VERSION 5.7 ;
  NOWIREEXTENSIONATPIN ON ;
  DIVIDERCHAR "/" ;
  BUSBITCHARS "[]" ;
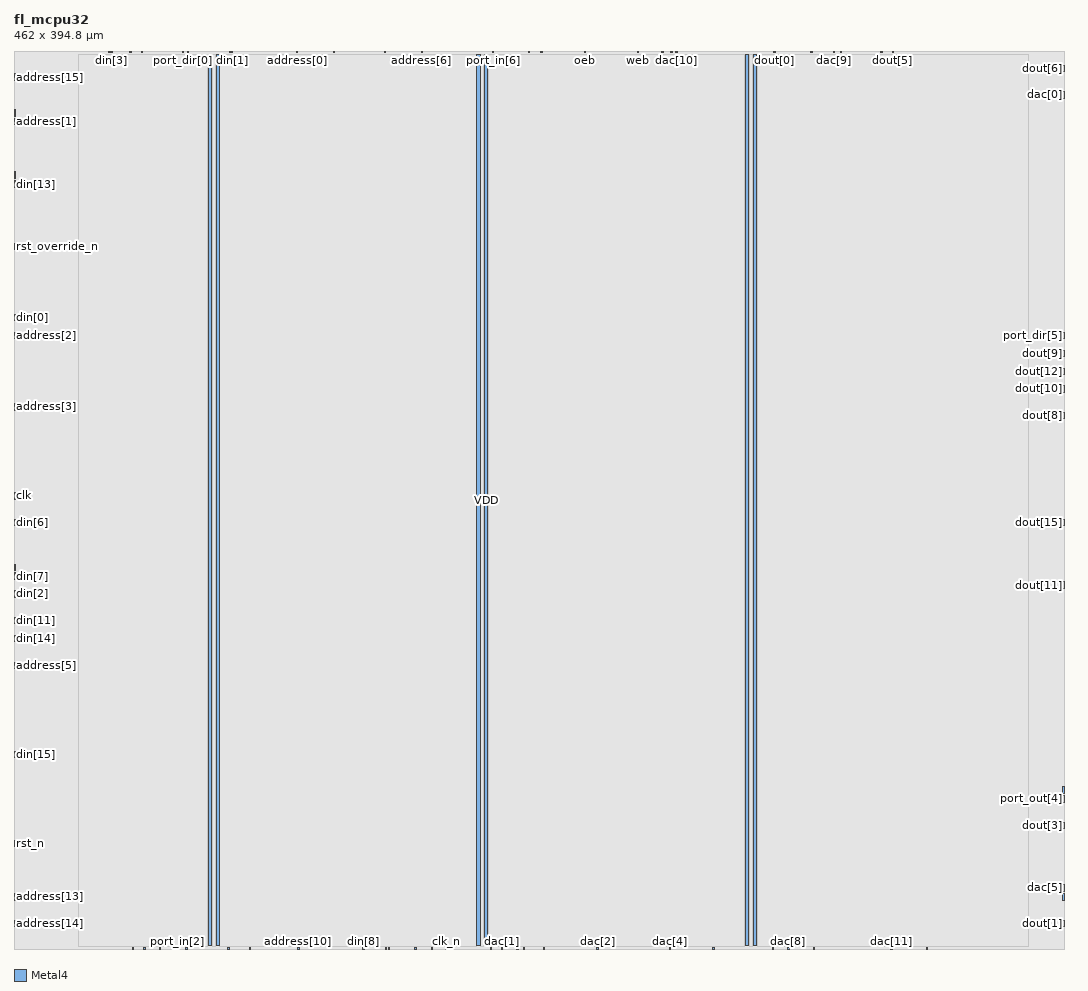
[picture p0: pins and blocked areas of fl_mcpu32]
MACRO fl_mcpu32
  CLASS BLOCK ;
  FOREIGN fl_mcpu32 ;
  ORIGIN 0.000 0.000 ;
  SIZE 462.000 BY 394.800 ;
  PIN VSS
    DIRECTION INOUT ;
    USE GROUND ;
    PORT
      LAYER Metal4 ;
        RECT 85.540 1.400 86.940 393.400 ;
    END
    PORT
      LAYER Metal4 ;
        RECT 203.700 1.400 205.100 393.400 ;
    END
    PORT
      LAYER Metal4 ;
        RECT 321.860 1.400 323.260 393.400 ;
    END
  END VSS
  PIN VDD
    DIRECTION INOUT ;
    USE POWER ;
    PORT
      LAYER Metal4 ;
        RECT 88.900 1.400 90.300 393.400 ;
    END
    PORT
      LAYER Metal4 ;
        RECT 207.060 1.400 208.460 393.400 ;
    END
    PORT
      LAYER Metal4 ;
        RECT 325.220 1.400 326.620 393.400 ;
    END
  END VDD
  PIN le
    DIRECTION OUTPUT ;
    USE SIGNAL ;
    ANTENNADIFFAREA 8.338300 ;
    PORT
      LAYER Metal4 ;
        RECT 162.960 394.240 163.520 394.800 ;
    END
  END le
  PIN oeb
    DIRECTION OUTPUT ;
    USE SIGNAL ;
    ANTENNADIFFAREA 8.338300 ;
    PORT
      LAYER Metal4 ;
        RECT 250.880 394.240 251.440 394.800 ;
    END
  END oeb
  PIN bus_enable
    DIRECTION OUTPUT ;
    USE SIGNAL ;
    ANTENNADIFFAREA 8.338300 ;
    PORT
      LAYER Metal4 ;
        RECT 140.560 394.240 141.120 394.800 ;
    END
  END bus_enable
  PIN web
    DIRECTION OUTPUT ;
    USE SIGNAL ;
    ANTENNADIFFAREA 8.338300 ;
    PORT
      LAYER Metal4 ;
        RECT 274.400 394.240 274.960 394.800 ;
    END
  END web
  PIN address[0]
    DIRECTION OUTPUT ;
    USE SIGNAL ;
    ANTENNADIFFAREA 8.338300 ;
    PORT
      LAYER Metal4 ;
        RECT 124.320 394.240 124.880 394.800 ;
    END
  END address[0]
  PIN address[15]
    DIRECTION OUTPUT ;
    USE SIGNAL ;
    ANTENNADIFFAREA 8.338300 ;
    PORT
      LAYER Metal4 ;
        RECT 0.000 382.200 0.560 385.000 ;
    END
  END address[15]
  PIN address[13]
    DIRECTION OUTPUT ;
    USE SIGNAL ;
    ANTENNADIFFAREA 8.338300 ;
    PORT
      LAYER Metal4 ;
        RECT 0.000 21.560 0.560 24.360 ;
    END
  END address[13]
  PIN address[14]
    DIRECTION OUTPUT ;
    USE SIGNAL ;
    ANTENNADIFFAREA 8.338300 ;
    PORT
      LAYER Metal4 ;
        RECT 0.000 9.800 0.560 12.600 ;
    END
  END address[14]
  PIN dout[0]
    DIRECTION OUTPUT ;
    USE SIGNAL ;
    ANTENNADIFFAREA 8.338300 ;
    PORT
      LAYER Metal4 ;
        RECT 334.320 394.240 334.880 394.800 ;
    END
  END dout[0]
  PIN dout[1]
    DIRECTION OUTPUT ;
    USE SIGNAL ;
    ANTENNADIFFAREA 8.338300 ;
    PORT
      LAYER Metal4 ;
        RECT 461.440 9.800 462.000 12.600 ;
    END
  END dout[1]
  PIN dout[2]
    DIRECTION OUTPUT ;
    USE SIGNAL ;
    ANTENNADIFFAREA 8.338300 ;
    PORT
      LAYER Metal4 ;
        RECT 461.440 68.600 462.000 71.400 ;
    END
  END dout[2]
  PIN dout[3]
    DIRECTION OUTPUT ;
    USE SIGNAL ;
    ANTENNADIFFAREA 8.338300 ;
    PORT
      LAYER Metal4 ;
        RECT 461.440 52.920 462.000 55.720 ;
    END
  END dout[3]
  PIN dout[4]
    DIRECTION OUTPUT ;
    USE SIGNAL ;
    ANTENNADIFFAREA 8.338300 ;
    PORT
      LAYER Metal4 ;
        RECT 176.400 0.000 176.960 0.560 ;
    END
  END dout[4]
  PIN dout[5]
    DIRECTION OUTPUT ;
    USE SIGNAL ;
    ANTENNADIFFAREA 8.338300 ;
    PORT
      LAYER Metal4 ;
        RECT 386.400 394.240 386.960 394.800 ;
    END
  END dout[5]
  PIN dout[6]
    DIRECTION OUTPUT ;
    USE SIGNAL ;
    ANTENNADIFFAREA 8.338300 ;
    PORT
      LAYER Metal4 ;
        RECT 461.440 386.120 462.000 388.920 ;
    END
  END dout[6]
  PIN dout[7]
    DIRECTION OUTPUT ;
    USE SIGNAL ;
    ANTENNADIFFAREA 8.338300 ;
    PORT
      LAYER Metal4 ;
        RECT 381.360 394.240 381.920 394.800 ;
    END
  END dout[7]
  PIN dout[10]
    DIRECTION OUTPUT ;
    USE SIGNAL ;
    ANTENNADIFFAREA 8.338300 ;
    PORT
      LAYER Metal4 ;
        RECT 461.440 245.000 462.000 247.800 ;
    END
  END dout[10]
  PIN dout[13]
    DIRECTION OUTPUT ;
    USE SIGNAL ;
    ANTENNADIFFAREA 8.338300 ;
    PORT
      LAYER Metal4 ;
        RECT 461.440 21.560 462.000 24.360 ;
    END
  END dout[13]
  PIN dout[14]
    DIRECTION OUTPUT ;
    USE SIGNAL ;
    ANTENNADIFFAREA 8.338300 ;
    PORT
      LAYER Metal4 ;
        RECT 363.440 394.240 364.000 394.800 ;
    END
  END dout[14]
  PIN dout[12]
    DIRECTION OUTPUT ;
    USE SIGNAL ;
    ANTENNADIFFAREA 8.338300 ;
    PORT
      LAYER Metal4 ;
        RECT 461.440 252.840 462.000 255.640 ;
    END
  END dout[12]
  PIN dout[11]
    DIRECTION OUTPUT ;
    USE SIGNAL ;
    ANTENNADIFFAREA 8.338300 ;
    PORT
      LAYER Metal4 ;
        RECT 461.440 158.760 462.000 161.560 ;
    END
  END dout[11]
  PIN dout[9]
    DIRECTION OUTPUT ;
    USE SIGNAL ;
    ANTENNADIFFAREA 8.338300 ;
    PORT
      LAYER Metal4 ;
        RECT 461.440 260.680 462.000 263.480 ;
    END
  END dout[9]
  PIN dout[8]
    DIRECTION OUTPUT ;
    USE SIGNAL ;
    ANTENNADIFFAREA 8.338300 ;
    PORT
      LAYER Metal4 ;
        RECT 461.440 233.240 462.000 236.040 ;
    END
  END dout[8]
  PIN dout[15]
    DIRECTION OUTPUT ;
    USE SIGNAL ;
    ANTENNADIFFAREA 8.338300 ;
    PORT
      LAYER Metal4 ;
        RECT 461.440 186.200 462.000 189.000 ;
    END
  END dout[15]
  PIN dac[11]
    DIRECTION OUTPUT ;
    USE SIGNAL ;
    ANTENNADIFFAREA 8.338300 ;
    PORT
      LAYER Metal4 ;
        RECT 385.840 0.000 386.400 0.560 ;
    END
  END dac[11]
  PIN dac[0]
    DIRECTION OUTPUT ;
    USE SIGNAL ;
    ANTENNADIFFAREA 8.338300 ;
    PORT
      LAYER Metal4 ;
        RECT 461.440 374.360 462.000 377.160 ;
    END
  END dac[0]
  PIN dac[3]
    DIRECTION OUTPUT ;
    USE SIGNAL ;
    ANTENNADIFFAREA 8.338300 ;
    PORT
      LAYER Metal4 ;
        RECT 224.000 0.000 224.560 0.560 ;
    END
  END dac[3]
  PIN dac[2]
    DIRECTION OUTPUT ;
    USE SIGNAL ;
    ANTENNADIFFAREA 8.338300 ;
    PORT
      LAYER Metal4 ;
        RECT 256.480 0.000 257.040 0.560 ;
    END
  END dac[2]
  PIN dac[1]
    DIRECTION OUTPUT ;
    USE SIGNAL ;
    ANTENNADIFFAREA 8.338300 ;
    PORT
      LAYER Metal4 ;
        RECT 214.480 0.000 215.040 0.560 ;
    END
  END dac[1]
  PIN port_dir[0]
    DIRECTION OUTPUT ;
    USE SIGNAL ;
    ANTENNADIFFAREA 8.338300 ;
    PORT
      LAYER Metal4 ;
        RECT 73.920 394.240 74.480 394.800 ;
    END
  END port_dir[0]
  PIN port_dir[1]
    DIRECTION OUTPUT ;
    USE SIGNAL ;
    ANTENNADIFFAREA 8.338300 ;
    PORT
      LAYER Metal4 ;
        RECT 232.960 0.000 233.520 0.560 ;
    END
  END port_dir[1]
  PIN port_dir[2]
    DIRECTION OUTPUT ;
    USE SIGNAL ;
    ANTENNADIFFAREA 8.338300 ;
    PORT
      LAYER Metal4 ;
        RECT 209.440 0.000 210.000 0.560 ;
    END
  END port_dir[2]
  PIN port_dir[3]
    DIRECTION OUTPUT ;
    USE SIGNAL ;
    ANTENNADIFFAREA 8.338300 ;
    PORT
      LAYER Metal4 ;
        RECT 401.520 0.000 402.080 0.560 ;
    END
  END port_dir[3]
  PIN port_dir[4]
    DIRECTION OUTPUT ;
    USE SIGNAL ;
    ANTENNADIFFAREA 8.338300 ;
    PORT
      LAYER Metal4 ;
        RECT 307.440 0.000 308.000 0.560 ;
    END
  END port_dir[4]
  PIN port_dir[5]
    DIRECTION OUTPUT ;
    USE SIGNAL ;
    ANTENNADIFFAREA 8.338300 ;
    PORT
      LAYER Metal4 ;
        RECT 461.440 268.520 462.000 271.320 ;
    END
  END port_dir[5]
  PIN port_dir[6]
    DIRECTION OUTPUT ;
    USE SIGNAL ;
    ANTENNADIFFAREA 8.338300 ;
    PORT
      LAYER Metal4 ;
        RECT 351.680 0.000 352.240 0.560 ;
    END
  END port_dir[6]
  PIN dac[9]
    DIRECTION OUTPUT ;
    USE SIGNAL ;
    ANTENNADIFFAREA 8.338300 ;
    PORT
      LAYER Metal4 ;
        RECT 360.640 394.240 361.200 394.800 ;
    END
  END dac[9]
  PIN dac[8]
    DIRECTION OUTPUT ;
    USE SIGNAL ;
    ANTENNADIFFAREA 8.338300 ;
    PORT
      LAYER Metal4 ;
        RECT 340.480 0.000 341.040 0.560 ;
    END
  END dac[8]
  PIN dac[7]
    DIRECTION OUTPUT ;
    USE SIGNAL ;
    ANTENNADIFFAREA 8.338300 ;
    PORT
      LAYER Metal4 ;
        RECT 285.040 394.240 285.600 394.800 ;
    END
  END dac[7]
  PIN dac[6]
    DIRECTION OUTPUT ;
    USE SIGNAL ;
    ANTENNADIFFAREA 8.338300 ;
    PORT
      LAYER Metal4 ;
        RECT 221.200 0.000 221.760 0.560 ;
    END
  END dac[6]
  PIN dac[5]
    DIRECTION OUTPUT ;
    USE SIGNAL ;
    ANTENNADIFFAREA 8.338300 ;
    PORT
      LAYER Metal4 ;
        RECT 461.440 25.480 462.000 28.280 ;
    END
  END dac[5]
  PIN dac[4]
    DIRECTION OUTPUT ;
    USE SIGNAL ;
    ANTENNADIFFAREA 8.338300 ;
    PORT
      LAYER Metal4 ;
        RECT 288.400 0.000 288.960 0.560 ;
    END
  END dac[4]
  PIN dac[10]
    DIRECTION OUTPUT ;
    USE SIGNAL ;
    ANTENNADIFFAREA 8.338300 ;
    PORT
      LAYER Metal4 ;
        RECT 291.200 394.240 291.760 394.800 ;
    END
  END dac[10]
  PIN address[12]
    DIRECTION OUTPUT ;
    USE SIGNAL ;
    ANTENNADIFFAREA 8.338300 ;
    PORT
      LAYER Metal4 ;
        RECT 63.840 0.000 64.400 0.560 ;
    END
  END address[12]
  PIN address[7]
    DIRECTION OUTPUT ;
    USE SIGNAL ;
    ANTENNADIFFAREA 8.338300 ;
    PORT
      LAYER Metal4 ;
        RECT 76.160 394.240 76.720 394.800 ;
    END
  END address[7]
  PIN address[3]
    DIRECTION OUTPUT ;
    USE SIGNAL ;
    ANTENNADIFFAREA 8.338300 ;
    PORT
      LAYER Metal4 ;
        RECT 0.000 237.160 0.560 239.960 ;
    END
  END address[3]
  PIN address[5]
    DIRECTION OUTPUT ;
    USE SIGNAL ;
    ANTENNADIFFAREA 8.338300 ;
    PORT
      LAYER Metal4 ;
        RECT 0.000 123.480 0.560 126.280 ;
    END
  END address[5]
  PIN address[9]
    DIRECTION OUTPUT ;
    USE SIGNAL ;
    ANTENNADIFFAREA 8.338300 ;
    PORT
      LAYER Metal4 ;
        RECT 52.080 0.000 52.640 0.560 ;
    END
  END address[9]
  PIN address[8]
    DIRECTION OUTPUT ;
    USE SIGNAL ;
    ANTENNADIFFAREA 8.338300 ;
    PORT
      LAYER Metal4 ;
        RECT 0.000 366.520 0.560 369.320 ;
    END
  END address[8]
  PIN address[6]
    DIRECTION OUTPUT ;
    USE SIGNAL ;
    ANTENNADIFFAREA 8.338300 ;
    PORT
      LAYER Metal4 ;
        RECT 179.200 394.240 179.760 394.800 ;
    END
  END address[6]
  PIN address[11]
    DIRECTION OUTPUT ;
    USE SIGNAL ;
    ANTENNADIFFAREA 8.338300 ;
    PORT
      LAYER Metal4 ;
        RECT 41.440 394.240 42.000 394.800 ;
    END
  END address[11]
  PIN address[2]
    DIRECTION OUTPUT ;
    USE SIGNAL ;
    ANTENNADIFFAREA 8.338300 ;
    PORT
      LAYER Metal4 ;
        RECT 0.000 268.520 0.560 271.320 ;
    END
  END address[2]
  PIN port_out[0]
    DIRECTION OUTPUT ;
    USE SIGNAL ;
    ANTENNADIFFAREA 8.338300 ;
    PORT
      LAYER Metal4 ;
        RECT 231.840 394.240 232.400 394.800 ;
    END
  END port_out[0]
  PIN port_out[1]
    DIRECTION OUTPUT ;
    USE SIGNAL ;
    ANTENNADIFFAREA 8.338300 ;
    PORT
      LAYER Metal4 ;
        RECT 57.120 0.000 57.680 0.560 ;
    END
  END port_out[1]
  PIN port_out[2]
    DIRECTION OUTPUT ;
    USE SIGNAL ;
    ANTENNADIFFAREA 8.338300 ;
    PORT
      LAYER Metal4 ;
        RECT 333.760 0.000 334.320 0.560 ;
    END
  END port_out[2]
  PIN port_out[3]
    DIRECTION OUTPUT ;
    USE SIGNAL ;
    ANTENNADIFFAREA 8.338300 ;
    PORT
      LAYER Metal4 ;
        RECT 288.960 394.240 289.520 394.800 ;
    END
  END port_out[3]
  PIN port_out[4]
    DIRECTION OUTPUT ;
    USE SIGNAL ;
    ANTENNADIFFAREA 8.338300 ;
    PORT
      LAYER Metal4 ;
        RECT 461.440 64.680 462.000 67.480 ;
    END
  END port_out[4]
  PIN port_out[5]
    DIRECTION OUTPUT ;
    USE SIGNAL ;
    ANTENNADIFFAREA 8.338300 ;
    PORT
      LAYER Metal4 ;
        RECT 226.240 394.240 226.800 394.800 ;
    END
  END port_out[5]
  PIN port_out[6]
    DIRECTION OUTPUT ;
    USE SIGNAL ;
    ANTENNADIFFAREA 8.338300 ;
    PORT
      LAYER Metal4 ;
        RECT 163.520 0.000 164.080 0.560 ;
    END
  END port_out[6]
  PIN address[1]
    DIRECTION OUTPUT ;
    USE SIGNAL ;
    ANTENNADIFFAREA 8.338300 ;
    PORT
      LAYER Metal4 ;
        RECT 0.000 362.600 0.560 365.400 ;
    END
  END address[1]
  PIN address[4]
    DIRECTION OUTPUT ;
    USE SIGNAL ;
    ANTENNADIFFAREA 8.338300 ;
    PORT
      LAYER Metal4 ;
        RECT 94.640 394.240 95.200 394.800 ;
    END
  END address[4]
  PIN address[10]
    DIRECTION OUTPUT ;
    USE SIGNAL ;
    ANTENNADIFFAREA 8.338300 ;
    PORT
      LAYER Metal4 ;
        RECT 124.880 0.000 125.440 0.560 ;
    END
  END address[10]
  PIN port_in[4]
    DIRECTION INPUT ;
    USE SIGNAL ;
    ANTENNAGATEAREA 1.999200 ;
    ANTENNADIFFAREA 0.877000 ;
    PORT
      LAYER Metal4 ;
        RECT 183.680 0.000 184.240 0.560 ;
    END
  END port_in[4]
  PIN port_in[0]
    DIRECTION INPUT ;
    USE SIGNAL ;
    ANTENNAGATEAREA 1.999200 ;
    ANTENNADIFFAREA 0.877000 ;
    PORT
      LAYER Metal4 ;
        RECT 350.560 394.240 351.120 394.800 ;
    END
  END port_in[0]
  PIN port_in[3]
    DIRECTION INPUT ;
    USE SIGNAL ;
    ANTENNAGATEAREA 1.999200 ;
    ANTENNADIFFAREA 0.877000 ;
    PORT
      LAYER Metal4 ;
        RECT 164.640 0.000 165.200 0.560 ;
    END
  END port_in[3]
  PIN port_in[6]
    DIRECTION INPUT ;
    USE SIGNAL ;
    ANTENNAGATEAREA 1.999200 ;
    ANTENNADIFFAREA 0.877000 ;
    PORT
      LAYER Metal4 ;
        RECT 210.560 394.240 211.120 394.800 ;
    END
  END port_in[6]
  PIN din[8]
    DIRECTION INPUT ;
    USE SIGNAL ;
    ANTENNAGATEAREA 1.999200 ;
    ANTENNADIFFAREA 0.877000 ;
    PORT
      LAYER Metal4 ;
        RECT 153.440 0.000 154.000 0.560 ;
    END
  END din[8]
  PIN din[6]
    DIRECTION INPUT ;
    USE SIGNAL ;
    ANTENNAGATEAREA 1.999200 ;
    ANTENNADIFFAREA 0.877000 ;
    PORT
      LAYER Metal4 ;
        RECT 0.000 186.200 0.560 189.000 ;
    END
  END din[6]
  PIN clk_n
    DIRECTION INPUT ;
    USE SIGNAL ;
    ANTENNAGATEAREA 2.352000 ;
    ANTENNADIFFAREA 0.877000 ;
    PORT
      LAYER Metal4 ;
        RECT 189.840 0.000 190.400 0.560 ;
    END
  END clk_n
  PIN rst_override_n
    DIRECTION INPUT ;
    USE SIGNAL ;
    ANTENNAGATEAREA 1.999200 ;
    ANTENNADIFFAREA 0.877000 ;
    PORT
      LAYER Metal4 ;
        RECT 0.000 307.720 0.560 310.520 ;
    END
  END rst_override_n
  PIN rst_n
    DIRECTION INPUT ;
    USE SIGNAL ;
    ANTENNAGATEAREA 1.999200 ;
    ANTENNADIFFAREA 0.877000 ;
    PORT
      LAYER Metal4 ;
        RECT 0.000 45.080 0.560 47.880 ;
    END
  END rst_n
  PIN port_in[2]
    DIRECTION INPUT ;
    USE SIGNAL ;
    ANTENNAGATEAREA 1.999200 ;
    ANTENNADIFFAREA 0.877000 ;
    PORT
      LAYER Metal4 ;
        RECT 71.680 0.000 72.240 0.560 ;
    END
  END port_in[2]
  PIN din[4]
    DIRECTION INPUT ;
    USE SIGNAL ;
    ANTENNAGATEAREA 1.999200 ;
    ANTENNADIFFAREA 0.877000 ;
    PORT
      LAYER Metal4 ;
        RECT 103.600 0.000 104.160 0.560 ;
    END
  END din[4]
  PIN din[12]
    DIRECTION INPUT ;
    USE SIGNAL ;
    ANTENNAGATEAREA 1.999200 ;
    ANTENNADIFFAREA 0.877000 ;
    PORT
      LAYER Metal4 ;
        RECT 75.600 0.000 76.160 0.560 ;
    END
  END din[12]
  PIN port_in[1]
    DIRECTION INPUT ;
    USE SIGNAL ;
    ANTENNAGATEAREA 1.999200 ;
    ANTENNADIFFAREA 0.877000 ;
    PORT
      LAYER Metal4 ;
        RECT 94.080 0.000 94.640 0.560 ;
    END
  END port_in[1]
  PIN din[5]
    DIRECTION INPUT ;
    USE SIGNAL ;
    ANTENNAGATEAREA 1.999200 ;
    ANTENNADIFFAREA 0.877000 ;
    PORT
      LAYER Metal4 ;
        RECT 56.000 394.240 56.560 394.800 ;
    END
  END din[5]
  PIN din[1]
    DIRECTION INPUT ;
    USE SIGNAL ;
    ANTENNAGATEAREA 1.999200 ;
    ANTENNADIFFAREA 0.877000 ;
    PORT
      LAYER Metal4 ;
        RECT 95.760 394.240 96.320 394.800 ;
    END
  END din[1]
  PIN din[3]
    DIRECTION INPUT ;
    USE SIGNAL ;
    ANTENNAGATEAREA 1.999200 ;
    ANTENNADIFFAREA 0.877000 ;
    PORT
      LAYER Metal4 ;
        RECT 42.560 394.240 43.120 394.800 ;
    END
  END din[3]
  PIN din[14]
    DIRECTION INPUT ;
    USE SIGNAL ;
    ANTENNAGATEAREA 1.999200 ;
    ANTENNADIFFAREA 0.877000 ;
    PORT
      LAYER Metal4 ;
        RECT 0.000 135.240 0.560 138.040 ;
    END
  END din[14]
  PIN din[13]
    DIRECTION INPUT ;
    USE SIGNAL ;
    ANTENNAGATEAREA 1.999200 ;
    ANTENNADIFFAREA 0.877000 ;
    PORT
      LAYER Metal4 ;
        RECT 0.000 335.160 0.560 337.960 ;
    END
  END din[13]
  PIN port_in[5]
    DIRECTION INPUT ;
    USE SIGNAL ;
    ANTENNAGATEAREA 1.999200 ;
    ANTENNADIFFAREA 0.877000 ;
    PORT
      LAYER Metal4 ;
        RECT 50.960 394.240 51.520 394.800 ;
    END
  END port_in[5]
  PIN din[7]
    DIRECTION INPUT ;
    USE SIGNAL ;
    ANTENNAGATEAREA 1.999200 ;
    ANTENNADIFFAREA 0.877000 ;
    PORT
      LAYER Metal4 ;
        RECT 0.000 162.680 0.560 165.480 ;
    END
  END din[7]
  PIN din[15]
    DIRECTION INPUT ;
    USE SIGNAL ;
    ANTENNAGATEAREA 1.999200 ;
    ANTENNADIFFAREA 0.877000 ;
    PORT
      LAYER Metal4 ;
        RECT 0.000 84.280 0.560 87.080 ;
    END
  END din[15]
  PIN din[9]
    DIRECTION INPUT ;
    USE SIGNAL ;
    ANTENNAGATEAREA 1.999200 ;
    ANTENNADIFFAREA 0.877000 ;
    PORT
      LAYER Metal4 ;
        RECT 0.000 339.080 0.560 341.880 ;
    END
  END din[9]
  PIN din[2]
    DIRECTION INPUT ;
    USE SIGNAL ;
    ANTENNAGATEAREA 1.999200 ;
    ANTENNADIFFAREA 0.877000 ;
    PORT
      LAYER Metal4 ;
        RECT 0.000 154.840 0.560 157.640 ;
    END
  END din[2]
  PIN din[0]
    DIRECTION INPUT ;
    USE SIGNAL ;
    ANTENNAGATEAREA 1.999200 ;
    ANTENNADIFFAREA 0.877000 ;
    PORT
      LAYER Metal4 ;
        RECT 0.000 276.360 0.560 279.160 ;
    END
  END din[0]
  PIN din[11]
    DIRECTION INPUT ;
    USE SIGNAL ;
    ANTENNAGATEAREA 1.999200 ;
    ANTENNADIFFAREA 0.877000 ;
    PORT
      LAYER Metal4 ;
        RECT 0.000 143.080 0.560 145.880 ;
    END
  END din[11]
  PIN clk
    DIRECTION INPUT ;
    USE SIGNAL ;
    ANTENNAGATEAREA 2.352000 ;
    ANTENNADIFFAREA 0.877000 ;
    PORT
      LAYER Metal4 ;
        RECT 0.000 197.960 0.560 200.760 ;
    END
  END clk
  PIN din[10]
    DIRECTION INPUT ;
    USE SIGNAL ;
    ANTENNAGATEAREA 1.999200 ;
    ANTENNADIFFAREA 0.877000 ;
    PORT
      LAYER Metal4 ;
        RECT 0.000 166.600 0.560 169.400 ;
    END
  END din[10]
  OBS
      LAYER Nwell ;
        RECT 0.970 0.970 461.030 393.830 ;
      LAYER Metal1 ;
        RECT 1.400 1.100 460.600 393.700 ;
      LAYER Metal2 ;
        RECT 0.000 0.000 462.000 394.800 ;
      LAYER Metal3 ;
        RECT 0.000 0.000 462.000 394.800 ;
      LAYER Metal4 ;
        RECT 28.420 1.120 85.240 393.680 ;
        RECT 87.240 1.120 88.600 393.680 ;
        RECT 90.600 1.120 203.400 393.680 ;
        RECT 205.400 1.120 206.760 393.680 ;
        RECT 208.760 1.120 321.560 393.680 ;
        RECT 323.560 1.120 324.920 393.680 ;
        RECT 326.920 1.120 446.460 393.680 ;
  END
END fl_mcpu32
END LIBRARY

